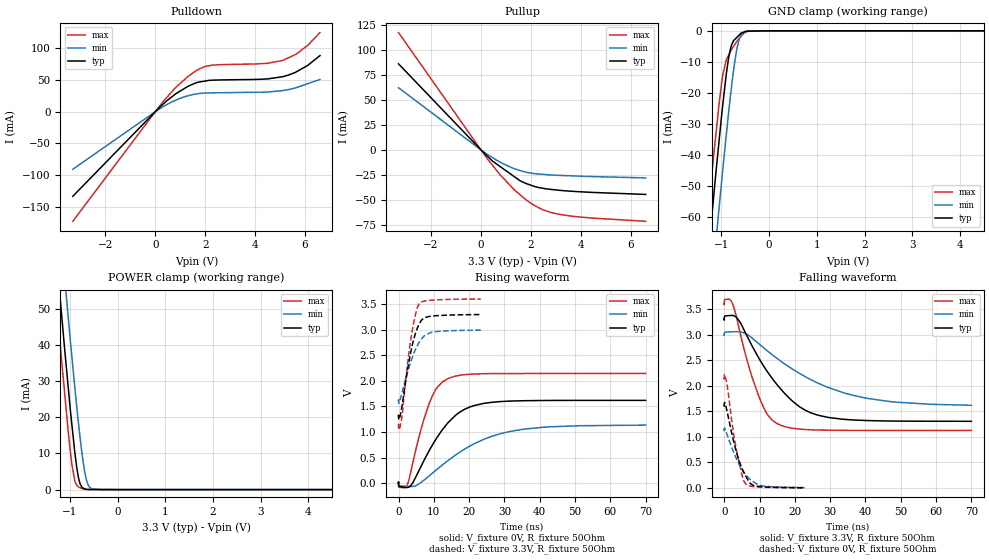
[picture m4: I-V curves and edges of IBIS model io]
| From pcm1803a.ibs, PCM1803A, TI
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|   io Model
[Model]   io
Model_type   I/O
Polarity   Non-Inverting
Enable   Active-Low
Vinl = 0.8
Vinh = 2
Vmeas = 1.65
Vref = 1.65
Cref = 20pF
Rref = 50
|   typ   min   max
C_comp   1.384e-12   1.327e-12   1.493e-12
[Voltage Range]   3.3   3   3.6
|Ambient Temperature   25   85   -40
|Junction Temperature
[Temperature Range]   27   125   -40
[Pullup Reference]   3.3   3   3.6
[Pulldown Reference]   0   0   0
[Power Clamp Reference]   3.3   3   3.6
[GND Clamp Reference]   0   0   0
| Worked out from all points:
|   slope of the pulldown table from 0 to 0.495 V, typ, clamps not added: 27.1 ohm
|   slope of the pullup table from 0 to 0.495 V, typ, clamps not added: 41.6 ohm
|   GND clamp passes 1 mA (typ) near -0.60 V on its own axis
|   POWER clamp passes 1 mA (typ) near -0.76 V on its own axis
|   falling waveform, V_fixture 3.3V, R_fixture 50Ohm: 20-80 % time 12.3ns typ, 21ns min, 6.6ns max; typ from 3.3 V to 1.3 V
|   rising waveform, V_fixture 0V, R_fixture 50Ohm: 20-80 % time 9.34ns typ, 16ns min, 5.51ns max; typ from 0 V to 1.62 V
|   rising waveform, V_fixture 3.3V, R_fixture 50Ohm: 20-80 % time 3.26ns typ, 4.13ns min, 2.76ns max; typ from 1.3 V to 3.3 V
|   falling waveform, V_fixture 0V, R_fixture 50Ohm: 20-80 % time 3.96ns typ, 4.9ns min, 3.06ns max; typ from 1.62 V to 0.003 V
[Pulldown]
|   Voltage   I(typ)   I(min)   I(max)
-3.3V     -133.4mA   -90.72mA   -172.9mA
327.6mV   12.54mA    8.343mA    16.53mA
831.6mV   28.63mA    18.43mA    38.64mA
1.307V    40.04mA    25.21mA    55.48mA
1.709V    46.6mA     28.52mA    66.3mA
2.023V    48.66mA    29.59mA    71.81mA
2.477V    50.09mA    29.97mA    74.11mA
4.471V    51.8mA     31.16mA    76.39mA
5.112V    55.45mA    33.43mA    81.12mA
5.648V    62.91mA    38.1mA     90.94mA
6.116V    73.42mA    44.41mA    105mA
6.6V      88.67mA    50.94mA    125mA
[GND Clamp]
|   Voltage   I(typ)   I(min)   I(max)
-3.3V     -425.4mA   -446.4mA   -412.3mA
-1.35V    -84.67mA   -106.9mA   -70.77mA
-1.287V   -73.99mA   -96.34mA   -60.5mA
-1.177V   -55.98mA   -78.07mA   -42.6mA
-1.112V   -45.31mA   -67.5mA    -32.95mA
-1.051V   -35.92mA   -57.65mA   -23.93mA
-968.4mV  -23.57mA   -44.44mA   -14.04mA
-821.7mV  -6.559mA   -22.64mA   -7.076mA
-729mV    -2.925mA   -10.93mA   -4.63mA
-648mV    -1.671mA   -3.869mA   -2.781mA
-513mV    -309.1uA   -288.5uA   -605.4uA
6.6V      0A         0A         0A
[Pullup]
|   Voltage   I(typ)   I(min)   I(max)
-3.3V     86.28mA    62.29mA    117.7mA
327.6mV   -8.113mA   -5.747mA   -11.25mA
788.4mV   -17.13mA   -12.63mA   -25.59mA
1.332V    -26.84mA   -18.84mA   -40.05mA
1.558V    -30.87mA   -20.77mA   -44.87mA
1.818V    -33.93mA   -22.5mA    -50.44mA
2.477V    -38.59mA   -24.64mA   -60.13mA
2.826V    -39.79mA   -25.27mA   -63.06mA
3.244V    -40.9mA    -25.77mA   -65.21mA
4.471V    -42.77mA   -26.88mA   -68.54mA
6.6V      -44.8mA    -28.2mA    -71.76mA
[POWER Clamp]
|   Voltage   I(typ)   I(min)   I(max)
-3.3V     383.3mA    401.4mA    372mA
-1.29V    65.4mA     85.28mA    53mA
-1.17V    47.45mA    67.1mA     34.83mA
-1.112V   38.83mA    58.6mA     26.66mA
-1.04V    28.74mA    48.12mA    16.53mA
-957.6mV  17.61mA    36.36mA    6.693mA
-896.4mV  10.01mA    27.9mA     2.266mA
-818.4mV  3.042mA    17.89mA    731.1uA
-738mV    520.6uA    8.928mA    235.6uA
-660mV    87.4uA     2.929mA    77.48uA
-540mV    35.84uA    208.1uA    2.265uA
6.6V      0A         0A         0A
[Ramp]
R_load = 50
|   typ   min   max
dV/dt_r   0.971845/9.31399e-09   0.68127/1.59495e-08   1.28722/5.51328e-09
dV/dt_f   1.19845/1.22907e-08   0.830496/2.08979e-08   1.48526/6.59526e-09
[Falling Waveform]
V_fixture = 3.3V
V_fixture_min = 3V
V_fixture_max = 3.6V
R_fixture = 50Ohm
|   Time   V(typ)   V(min)   V(max)
0s        3.3V       3V         3.6V
2.248ns   3.373V     3.053V     3.619V
4.324ns   3.258V     3.053V     3.085V
9.624ns   2.559V     2.83V      1.823V
12.41ns   2.254V     2.669V     1.419V
15.12ns   2.006V     2.524V     1.253V
21.54ns   1.577V     2.23V      1.149V
29.62ns   1.377V     1.96V      1.128V
46.42ns   1.308V     1.693V     1.125V
70ns      1.303V     1.616V     1.125V
[Rising Waveform]
V_fixture = 0V
V_fixture_min = 0V
V_fixture_max = 0V
R_fixture = 50Ohm
|   Time   V(typ)   V(min)   V(max)
0s        0V         0V         0V
140ps     -64.58mV   -49.28mV   -78.9mV
2.468ns   -85.15mV   -63.57mV   -32.83mV
4.032ns   6.077mV    -63.93mV   396.1mV
8.628ns   629.9mV    139.5mV    1.545V
10.98ns   901.7mV    275.7mV    1.875V
14.13ns   1.191V     448.8mV    2.05V
20.14ns   1.489V     723.7mV    2.131V
31.64ns   1.606V     1.013V     2.145V
70ns      1.62V      1.135V     2.145V
[Rising Waveform]
V_fixture = 3.3V
V_fixture_min = 3V
V_fixture_max = 3.6V
R_fixture = 50Ohm
|   Time   V(typ)   V(min)   V(max)
0s        1.302V     1.604V     1.125V
140ps     1.245V     1.565V     1.048V
900ps     1.473V     1.75V      1.262V
2.32ns    2.12V      2.118V     2.189V
3.688ns   2.634V     2.418V     2.903V
4.912ns   2.955V     2.633V     3.33V
5.812ns   3.103V     2.752V     3.505V
6.824ns   3.208V     2.849V     3.552V
9.368ns   3.268V     2.952V     3.579V
23.32ns   3.298V     2.994V     3.6V
[Falling Waveform]
V_fixture = 0V
V_fixture_min = 0V
V_fixture_max = 0V
R_fixture = 50Ohm
|   Time   V(typ)   V(min)   V(max)
0s        1.62V      1.137V     2.145V
140ps     1.668V     1.168V     2.216V
896ps     1.469V     1.027V     1.976V
2.316ns   1.014V     756.4mV    1.216V
3.488ns   692.8mV    565.4mV    728.8mV
5.3ns     338.2mV    332.9mV    182.8mV
6.032ns   239.9mV    261.4mV    82.14mV
7.404ns   87.74mV    161.4mV    33.55mV
9.364ns   32.23mV    71.76mV    18.56mV
22.79ns   2.968mV    6.96mV     695.3uV
